VERSION 5.7 ;
  NOWIREEXTENSIONATPIN ON ;
  DIVIDERCHAR "/" ;
  BUSBITCHARS "[]" ;
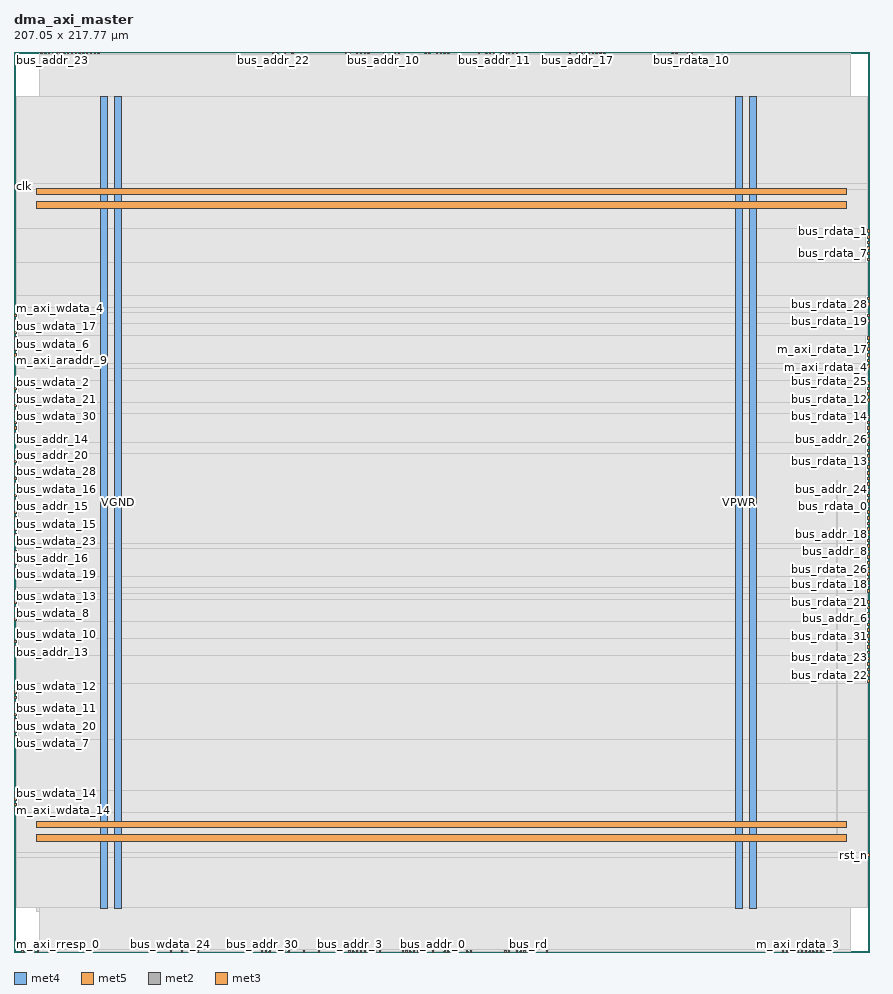
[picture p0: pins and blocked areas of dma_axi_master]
MACRO dma_axi_master
  CLASS BLOCK ;
  FOREIGN dma_axi_master ;
  ORIGIN 0.000 0.000 ;
  SIZE 207.050 BY 217.770 ;
  PIN VGND
    DIRECTION INOUT ;
    USE GROUND ;
    PORT
      LAYER met4 ;
        RECT 24.340 10.640 25.940 206.960 ;
    END
    PORT
      LAYER met4 ;
        RECT 177.940 10.640 179.540 206.960 ;
    END
    PORT
      LAYER met5 ;
        RECT 5.520 30.030 201.480 31.630 ;
    END
    PORT
      LAYER met5 ;
        RECT 5.520 183.210 201.480 184.810 ;
    END
  END VGND
  PIN VPWR
    DIRECTION INOUT ;
    USE POWER ;
    PORT
      LAYER met4 ;
        RECT 21.040 10.640 22.640 206.960 ;
    END
    PORT
      LAYER met4 ;
        RECT 174.640 10.640 176.240 206.960 ;
    END
    PORT
      LAYER met5 ;
        RECT 5.520 26.730 201.480 28.330 ;
    END
    PORT
      LAYER met5 ;
        RECT 5.520 179.910 201.480 181.510 ;
    END
  END VPWR
  PIN bus_addr_0
    DIRECTION INPUT ;
    USE SIGNAL ;
    ANTENNAGATEAREA 0.647700 ;
    ANTENNADIFFAREA 0.434700 ;
    PORT
      LAYER met2 ;
        RECT 101.290 0.000 101.570 0.280 ;
    END
  END bus_addr_0
  PIN bus_addr_1
    DIRECTION INPUT ;
    USE SIGNAL ;
    ANTENNAGATEAREA 0.647700 ;
    ANTENNADIFFAREA 0.434700 ;
    PORT
      LAYER met2 ;
        RECT 86.570 0.000 86.850 0.280 ;
    END
  END bus_addr_1
  PIN bus_addr_10
    DIRECTION INPUT ;
    USE SIGNAL ;
    ANTENNAGATEAREA 0.647700 ;
    ANTENNADIFFAREA 0.434700 ;
    PORT
      LAYER met2 ;
        RECT 89.330 217.490 89.610 217.770 ;
    END
  END bus_addr_10
  PIN bus_addr_11
    DIRECTION INPUT ;
    USE SIGNAL ;
    ANTENNAGATEAREA 0.647700 ;
    ANTENNADIFFAREA 0.434700 ;
    PORT
      LAYER met2 ;
        RECT 116.010 217.490 116.290 217.770 ;
    END
  END bus_addr_11
  PIN bus_addr_12
    DIRECTION INPUT ;
    USE SIGNAL ;
    ANTENNAGATEAREA 0.647700 ;
    ANTENNADIFFAREA 0.434700 ;
    PORT
      LAYER met2 ;
        RECT 99.450 217.490 99.730 217.770 ;
    END
  END bus_addr_12
  PIN bus_addr_13
    DIRECTION INPUT ;
    USE SIGNAL ;
    ANTENNAGATEAREA 0.647700 ;
    ANTENNADIFFAREA 0.434700 ;
    PORT
      LAYER met3 ;
        RECT 0.000 72.120 0.600 72.720 ;
    END
  END bus_addr_13
  PIN bus_addr_14
    DIRECTION INPUT ;
    USE SIGNAL ;
    ANTENNAGATEAREA 0.647700 ;
    ANTENNADIFFAREA 0.434700 ;
    PORT
      LAYER met3 ;
        RECT 0.000 123.800 0.600 124.400 ;
    END
  END bus_addr_14
  PIN bus_addr_15
    DIRECTION INPUT ;
    USE SIGNAL ;
    ANTENNAGATEAREA 0.647700 ;
    ANTENNADIFFAREA 0.434700 ;
    PORT
      LAYER met3 ;
        RECT 0.000 107.480 0.600 108.080 ;
    END
  END bus_addr_15
  PIN bus_addr_16
    DIRECTION INPUT ;
    USE SIGNAL ;
    ANTENNAGATEAREA 0.647700 ;
    ANTENNADIFFAREA 0.434700 ;
    PORT
      LAYER met3 ;
        RECT 0.000 96.600 0.600 97.200 ;
    END
  END bus_addr_16
  PIN bus_addr_17
    DIRECTION INPUT ;
    USE SIGNAL ;
    ANTENNAGATEAREA 0.647700 ;
    ANTENNADIFFAREA 0.434700 ;
    PORT
      LAYER met2 ;
        RECT 136.250 217.490 136.530 217.770 ;
    END
  END bus_addr_17
  PIN bus_addr_18
    DIRECTION INPUT ;
    USE SIGNAL ;
    ANTENNAGATEAREA 0.647700 ;
    ANTENNADIFFAREA 0.434700 ;
    PORT
      LAYER met3 ;
        RECT 206.450 100.680 207.050 101.280 ;
    END
  END bus_addr_18
  PIN bus_addr_19
    DIRECTION INPUT ;
    USE SIGNAL ;
    ANTENNAGATEAREA 0.647700 ;
    ANTENNADIFFAREA 0.434700 ;
    PORT
      LAYER met2 ;
        RECT 117.850 217.490 118.130 217.770 ;
    END
  END bus_addr_19
  PIN bus_addr_2
    DIRECTION INPUT ;
    USE SIGNAL ;
    ANTENNAGATEAREA 0.647700 ;
    ANTENNADIFFAREA 0.434700 ;
    PORT
      LAYER met2 ;
        RECT 106.810 0.000 107.090 0.280 ;
    END
  END bus_addr_2
  PIN bus_addr_20
    DIRECTION INPUT ;
    USE SIGNAL ;
    ANTENNAGATEAREA 0.647700 ;
    ANTENNADIFFAREA 0.434700 ;
    PORT
      LAYER met3 ;
        RECT 0.000 119.720 0.600 120.320 ;
    END
  END bus_addr_20
  PIN bus_addr_21
    DIRECTION INPUT ;
    USE SIGNAL ;
    ANTENNAGATEAREA 0.647700 ;
    ANTENNADIFFAREA 0.434700 ;
    PORT
      LAYER met2 ;
        RECT 138.090 217.490 138.370 217.770 ;
    END
  END bus_addr_21
  PIN bus_addr_22
    DIRECTION INPUT ;
    USE SIGNAL ;
    ANTENNAGATEAREA 0.647700 ;
    ANTENNADIFFAREA 0.434700 ;
    PORT
      LAYER met2 ;
        RECT 62.650 217.490 62.930 217.770 ;
    END
  END bus_addr_22
  PIN bus_addr_23
    DIRECTION INPUT ;
    USE SIGNAL ;
    ANTENNAGATEAREA 0.647700 ;
    ANTENNADIFFAREA 0.434700 ;
    PORT
      LAYER met2 ;
        RECT 6.530 217.490 6.810 217.770 ;
    END
  END bus_addr_23
  PIN bus_addr_24
    DIRECTION INPUT ;
    USE SIGNAL ;
    ANTENNAGATEAREA 0.647700 ;
    ANTENNADIFFAREA 0.434700 ;
    PORT
      LAYER met3 ;
        RECT 206.450 111.560 207.050 112.160 ;
    END
  END bus_addr_24
  PIN bus_addr_25
    DIRECTION INPUT ;
    USE SIGNAL ;
    ANTENNAGATEAREA 0.647700 ;
    ANTENNADIFFAREA 0.434700 ;
    PORT
      LAYER met2 ;
        RECT 112.330 217.490 112.610 217.770 ;
    END
  END bus_addr_25
  PIN bus_addr_26
    DIRECTION INPUT ;
    USE SIGNAL ;
    ANTENNAGATEAREA 0.647700 ;
    ANTENNADIFFAREA 0.434700 ;
    PORT
      LAYER met3 ;
        RECT 206.450 123.800 207.050 124.400 ;
    END
  END bus_addr_26
  PIN bus_addr_27
    DIRECTION INPUT ;
    USE SIGNAL ;
    ANTENNAGATEAREA 0.647700 ;
    ANTENNADIFFAREA 0.434700 ;
    PORT
      LAYER met2 ;
        RECT 80.130 217.490 80.410 217.770 ;
    END
  END bus_addr_27
  PIN bus_addr_28
    DIRECTION INPUT ;
    USE SIGNAL ;
    ANTENNAGATEAREA 0.647700 ;
    ANTENNADIFFAREA 0.434700 ;
    PORT
      LAYER met2 ;
        RECT 134.410 217.490 134.690 217.770 ;
    END
  END bus_addr_28
  PIN bus_addr_29
    DIRECTION INPUT ;
    USE SIGNAL ;
    ANTENNAGATEAREA 0.647700 ;
    ANTENNADIFFAREA 0.434700 ;
    PORT
      LAYER met2 ;
        RECT 81.050 217.490 81.330 217.770 ;
    END
  END bus_addr_29
  PIN bus_addr_3
    DIRECTION INPUT ;
    USE SIGNAL ;
    ANTENNAGATEAREA 0.647700 ;
    ANTENNADIFFAREA 0.434700 ;
    PORT
      LAYER met2 ;
        RECT 81.050 0.000 81.330 0.280 ;
    END
  END bus_addr_3
  PIN bus_addr_30
    DIRECTION INPUT ;
    USE SIGNAL ;
    ANTENNAGATEAREA 0.647700 ;
    ANTENNADIFFAREA 0.434700 ;
    PORT
      LAYER met2 ;
        RECT 59.890 0.000 60.170 0.280 ;
    END
  END bus_addr_30
  PIN bus_addr_31
    DIRECTION INPUT ;
    USE SIGNAL ;
    ANTENNAGATEAREA 0.647700 ;
    ANTENNADIFFAREA 0.434700 ;
    PORT
      LAYER met2 ;
        RECT 100.370 217.490 100.650 217.770 ;
    END
  END bus_addr_31
  PIN bus_addr_4
    DIRECTION INPUT ;
    USE SIGNAL ;
    ANTENNAGATEAREA 0.647700 ;
    ANTENNADIFFAREA 0.434700 ;
    PORT
      LAYER met2 ;
        RECT 81.970 0.000 82.250 0.280 ;
    END
  END bus_addr_4
  PIN bus_addr_5
    DIRECTION INPUT ;
    USE SIGNAL ;
    ANTENNAGATEAREA 0.647700 ;
    ANTENNADIFFAREA 0.434700 ;
    PORT
      LAYER met2 ;
        RECT 121.530 0.000 121.810 0.280 ;
    END
  END bus_addr_5
  PIN bus_addr_6
    DIRECTION INPUT ;
    USE SIGNAL ;
    ANTENNAGATEAREA 0.647700 ;
    ANTENNADIFFAREA 0.434700 ;
    PORT
      LAYER met3 ;
        RECT 206.450 80.280 207.050 80.880 ;
    END
  END bus_addr_6
  PIN bus_addr_7
    DIRECTION INPUT ;
    USE SIGNAL ;
    ANTENNAGATEAREA 0.647700 ;
    ANTENNADIFFAREA 0.434700 ;
    PORT
      LAYER met2 ;
        RECT 93.930 0.000 94.210 0.280 ;
    END
  END bus_addr_7
  PIN bus_addr_8
    DIRECTION INPUT ;
    USE SIGNAL ;
    ANTENNAGATEAREA 0.647700 ;
    ANTENNADIFFAREA 0.434700 ;
    PORT
      LAYER met3 ;
        RECT 206.450 96.600 207.050 97.200 ;
    END
  END bus_addr_8
  PIN bus_addr_9
    DIRECTION INPUT ;
    USE SIGNAL ;
    ANTENNAGATEAREA 0.647700 ;
    ANTENNADIFFAREA 0.434700 ;
    PORT
      LAYER met3 ;
        RECT 0.000 144.200 0.600 144.800 ;
    END
  END bus_addr_9
  PIN bus_rd
    DIRECTION INPUT ;
    USE SIGNAL ;
    ANTENNAGATEAREA 0.647700 ;
    ANTENNADIFFAREA 0.434700 ;
    PORT
      LAYER met2 ;
        RECT 124.290 0.000 124.570 0.280 ;
    END
  END bus_rd
  PIN bus_rdata_0
    DIRECTION OUTPUT ;
    USE SIGNAL ;
    ANTENNAGATEAREA 0.434700 ;
    ANTENNADIFFAREA 1.137600 ;
    PORT
      LAYER met3 ;
        RECT 206.450 107.480 207.050 108.080 ;
    END
  END bus_rdata_0
  PIN bus_rdata_1
    DIRECTION OUTPUT ;
    USE SIGNAL ;
    ANTENNAGATEAREA 0.434700 ;
    ANTENNADIFFAREA 1.137600 ;
    PORT
      LAYER met3 ;
        RECT 206.450 174.120 207.050 174.720 ;
    END
  END bus_rdata_1
  PIN bus_rdata_10
    DIRECTION OUTPUT ;
    USE SIGNAL ;
    ANTENNAGATEAREA 0.434700 ;
    ANTENNADIFFAREA 1.137600 ;
    PORT
      LAYER met2 ;
        RECT 163.850 217.490 164.130 217.770 ;
    END
  END bus_rdata_10
  PIN bus_rdata_11
    DIRECTION OUTPUT ;
    USE SIGNAL ;
    ANTENNAGATEAREA 0.434700 ;
    ANTENNADIFFAREA 1.137600 ;
    PORT
      LAYER met3 ;
        RECT 206.450 172.760 207.050 173.360 ;
    END
  END bus_rdata_11
  PIN bus_rdata_12
    DIRECTION OUTPUT ;
    USE SIGNAL ;
    ANTENNAGATEAREA 0.434700 ;
    ANTENNADIFFAREA 1.137600 ;
    PORT
      LAYER met3 ;
        RECT 206.450 133.320 207.050 133.920 ;
    END
  END bus_rdata_12
  PIN bus_rdata_13
    DIRECTION OUTPUT ;
    USE SIGNAL ;
    ANTENNAGATEAREA 0.434700 ;
    ANTENNADIFFAREA 1.137600 ;
    PORT
      LAYER met3 ;
        RECT 206.450 118.360 207.050 118.960 ;
    END
  END bus_rdata_13
  PIN bus_rdata_14
    DIRECTION OUTPUT ;
    USE SIGNAL ;
    ANTENNAGATEAREA 0.434700 ;
    ANTENNADIFFAREA 1.137600 ;
    PORT
      LAYER met3 ;
        RECT 206.450 129.240 207.050 129.840 ;
    END
  END bus_rdata_14
  PIN bus_rdata_15
    DIRECTION OUTPUT ;
    USE SIGNAL ;
    ANTENNAGATEAREA 0.434700 ;
    ANTENNADIFFAREA 1.137600 ;
    PORT
      LAYER met3 ;
        RECT 206.450 125.160 207.050 125.760 ;
    END
  END bus_rdata_15
  PIN bus_rdata_16
    DIRECTION OUTPUT ;
    USE SIGNAL ;
    ANTENNAGATEAREA 0.434700 ;
    ANTENNADIFFAREA 1.137600 ;
    PORT
      LAYER met2 ;
        RECT 196.050 0.000 196.330 0.280 ;
    END
  END bus_rdata_16
  PIN bus_rdata_17
    DIRECTION OUTPUT ;
    USE SIGNAL ;
    ANTENNAGATEAREA 0.434700 ;
    ANTENNADIFFAREA 1.137600 ;
    PORT
      LAYER met3 ;
        RECT 206.450 144.200 207.050 144.800 ;
    END
  END bus_rdata_17
  PIN bus_rdata_18
    DIRECTION OUTPUT ;
    USE SIGNAL ;
    ANTENNAGATEAREA 0.434700 ;
    ANTENNADIFFAREA 1.137600 ;
    PORT
      LAYER met3 ;
        RECT 206.450 87.080 207.050 87.680 ;
    END
  END bus_rdata_18
  PIN bus_rdata_19
    DIRECTION OUTPUT ;
    USE SIGNAL ;
    ANTENNAGATEAREA 0.434700 ;
    ANTENNADIFFAREA 1.137600 ;
    PORT
      LAYER met3 ;
        RECT 206.450 152.360 207.050 152.960 ;
    END
  END bus_rdata_19
  PIN bus_rdata_2
    DIRECTION OUTPUT ;
    USE SIGNAL ;
    ANTENNAGATEAREA 0.434700 ;
    ANTENNADIFFAREA 1.137600 ;
    PORT
      LAYER met3 ;
        RECT 206.450 104.760 207.050 105.360 ;
    END
  END bus_rdata_2
  PIN bus_rdata_20
    DIRECTION OUTPUT ;
    USE SIGNAL ;
    ANTENNAGATEAREA 0.434700 ;
    ANTENNADIFFAREA 1.137600 ;
    PORT
      LAYER met3 ;
        RECT 206.450 146.920 207.050 147.520 ;
    END
  END bus_rdata_20
  PIN bus_rdata_21
    DIRECTION OUTPUT ;
    USE SIGNAL ;
    ANTENNAGATEAREA 0.434700 ;
    ANTENNADIFFAREA 1.137600 ;
    PORT
      LAYER met3 ;
        RECT 206.450 84.360 207.050 84.960 ;
    END
  END bus_rdata_21
  PIN bus_rdata_22
    DIRECTION OUTPUT ;
    USE SIGNAL ;
    ANTENNAGATEAREA 0.434700 ;
    ANTENNADIFFAREA 1.137600 ;
    PORT
      LAYER met3 ;
        RECT 206.450 66.680 207.050 67.280 ;
    END
  END bus_rdata_22
  PIN bus_rdata_23
    DIRECTION OUTPUT ;
    USE SIGNAL ;
    ANTENNAGATEAREA 0.434700 ;
    ANTENNADIFFAREA 1.137600 ;
    PORT
      LAYER met3 ;
        RECT 206.450 69.400 207.050 70.000 ;
    END
  END bus_rdata_23
  PIN bus_rdata_24
    DIRECTION OUTPUT ;
    USE SIGNAL ;
    ANTENNAGATEAREA 0.434700 ;
    ANTENNADIFFAREA 1.137600 ;
    PORT
      LAYER met2 ;
        RECT 191.450 0.000 191.730 0.280 ;
    END
  END bus_rdata_24
  PIN bus_rdata_25
    DIRECTION OUTPUT ;
    USE SIGNAL ;
    ANTENNAGATEAREA 0.434700 ;
    ANTENNADIFFAREA 1.137600 ;
    PORT
      LAYER met3 ;
        RECT 206.450 136.040 207.050 136.640 ;
    END
  END bus_rdata_25
  PIN bus_rdata_26
    DIRECTION OUTPUT ;
    USE SIGNAL ;
    ANTENNAGATEAREA 0.434700 ;
    ANTENNADIFFAREA 1.137600 ;
    PORT
      LAYER met3 ;
        RECT 206.450 93.880 207.050 94.480 ;
    END
  END bus_rdata_26
  PIN bus_rdata_27
    DIRECTION OUTPUT ;
    USE SIGNAL ;
    ANTENNAGATEAREA 0.434700 ;
    ANTENNADIFFAREA 1.137600 ;
    PORT
      LAYER met2 ;
        RECT 162.930 217.490 163.210 217.770 ;
    END
  END bus_rdata_27
  PIN bus_rdata_28
    DIRECTION OUTPUT ;
    USE SIGNAL ;
    ANTENNAGATEAREA 0.434700 ;
    ANTENNADIFFAREA 1.137600 ;
    PORT
      LAYER met3 ;
        RECT 206.450 156.440 207.050 157.040 ;
    END
  END bus_rdata_28
  PIN bus_rdata_29
    DIRECTION OUTPUT ;
    USE SIGNAL ;
    ANTENNAGATEAREA 0.434700 ;
    ANTENNADIFFAREA 1.137600 ;
    PORT
      LAYER met3 ;
        RECT 206.450 70.760 207.050 71.360 ;
    END
  END bus_rdata_29
  PIN bus_rdata_3
    DIRECTION OUTPUT ;
    USE SIGNAL ;
    ANTENNAGATEAREA 0.434700 ;
    ANTENNADIFFAREA 1.137600 ;
    PORT
      LAYER met2 ;
        RECT 194.210 0.000 194.490 0.280 ;
    END
  END bus_rdata_3
  PIN bus_rdata_30
    DIRECTION OUTPUT ;
    USE SIGNAL ;
    ANTENNAGATEAREA 0.434700 ;
    ANTENNADIFFAREA 1.137600 ;
    PORT
      LAYER met2 ;
        RECT 193.290 0.000 193.570 0.280 ;
    END
  END bus_rdata_30
  PIN bus_rdata_31
    DIRECTION OUTPUT ;
    USE SIGNAL ;
    ANTENNAGATEAREA 0.434700 ;
    ANTENNADIFFAREA 1.137600 ;
    PORT
      LAYER met3 ;
        RECT 206.450 77.560 207.050 78.160 ;
    END
  END bus_rdata_31
  PIN bus_rdata_4
    DIRECTION OUTPUT ;
    USE SIGNAL ;
    ANTENNAGATEAREA 0.434700 ;
    ANTENNADIFFAREA 1.137600 ;
    PORT
      LAYER met3 ;
        RECT 206.450 141.480 207.050 142.080 ;
    END
  END bus_rdata_4
  PIN bus_rdata_5
    DIRECTION OUTPUT ;
    USE SIGNAL ;
    ANTENNAGATEAREA 0.434700 ;
    ANTENNADIFFAREA 1.137600 ;
    PORT
      LAYER met3 ;
        RECT 206.450 92.520 207.050 93.120 ;
    END
  END bus_rdata_5
  PIN bus_rdata_6
    DIRECTION OUTPUT ;
    USE SIGNAL ;
    ANTENNAGATEAREA 0.434700 ;
    ANTENNADIFFAREA 1.137600 ;
    PORT
      LAYER met3 ;
        RECT 206.450 108.840 207.050 109.440 ;
    END
  END bus_rdata_6
  PIN bus_rdata_7
    DIRECTION OUTPUT ;
    USE SIGNAL ;
    ANTENNAGATEAREA 0.434700 ;
    ANTENNADIFFAREA 1.137600 ;
    PORT
      LAYER met3 ;
        RECT 206.450 168.680 207.050 169.280 ;
    END
  END bus_rdata_7
  PIN bus_rdata_8
    DIRECTION OUTPUT ;
    USE SIGNAL ;
    ANTENNAGATEAREA 0.434700 ;
    ANTENNADIFFAREA 1.137600 ;
    PORT
      LAYER met3 ;
        RECT 206.450 73.480 207.050 74.080 ;
    END
  END bus_rdata_8
  PIN bus_rdata_9
    DIRECTION OUTPUT ;
    USE SIGNAL ;
    ANTENNAGATEAREA 0.434700 ;
    ANTENNADIFFAREA 1.137600 ;
    PORT
      LAYER met3 ;
        RECT 206.450 115.640 207.050 116.240 ;
    END
  END bus_rdata_9
  PIN bus_ready
    DIRECTION OUTPUT ;
    USE SIGNAL ;
    PORT
      LAYER met2 ;
        RECT 1.930 0.000 2.210 0.280 ;
    END
  END bus_ready
  PIN bus_wdata_0
    DIRECTION INPUT ;
    USE SIGNAL ;
    ANTENNAGATEAREA 0.647700 ;
    ANTENNADIFFAREA 0.434700 ;
    PORT
      LAYER met2 ;
        RECT 18.490 217.490 18.770 217.770 ;
    END
  END bus_wdata_0
  PIN bus_wdata_1
    DIRECTION INPUT ;
    USE SIGNAL ;
    ANTENNAGATEAREA 0.647700 ;
    ANTENNADIFFAREA 0.434700 ;
    PORT
      LAYER met3 ;
        RECT 0.000 99.320 0.600 99.920 ;
    END
  END bus_wdata_1
  PIN bus_wdata_10
    DIRECTION INPUT ;
    USE SIGNAL ;
    ANTENNAGATEAREA 0.647700 ;
    ANTENNADIFFAREA 0.434700 ;
    PORT
      LAYER met3 ;
        RECT 0.000 74.840 0.600 75.440 ;
    END
  END bus_wdata_10
  PIN bus_wdata_11
    DIRECTION INPUT ;
    USE SIGNAL ;
    ANTENNAGATEAREA 0.647700 ;
    ANTENNADIFFAREA 0.434700 ;
    PORT
      LAYER met3 ;
        RECT 0.000 58.520 0.600 59.120 ;
    END
  END bus_wdata_11
  PIN bus_wdata_12
    DIRECTION INPUT ;
    USE SIGNAL ;
    ANTENNAGATEAREA 0.647700 ;
    ANTENNADIFFAREA 0.434700 ;
    PORT
      LAYER met3 ;
        RECT 0.000 63.960 0.600 64.560 ;
    END
  END bus_wdata_12
  PIN bus_wdata_13
    DIRECTION INPUT ;
    USE SIGNAL ;
    ANTENNAGATEAREA 0.647700 ;
    ANTENNADIFFAREA 0.434700 ;
    PORT
      LAYER met3 ;
        RECT 0.000 85.720 0.600 86.320 ;
    END
  END bus_wdata_13
  PIN bus_wdata_14
    DIRECTION INPUT ;
    USE SIGNAL ;
    ANTENNAGATEAREA 0.647700 ;
    ANTENNADIFFAREA 0.434700 ;
    PORT
      LAYER met3 ;
        RECT 0.000 38.120 0.600 38.720 ;
    END
  END bus_wdata_14
  PIN bus_wdata_15
    DIRECTION INPUT ;
    USE SIGNAL ;
    ANTENNAGATEAREA 0.647700 ;
    ANTENNADIFFAREA 0.434700 ;
    PORT
      LAYER met3 ;
        RECT 0.000 104.760 0.600 105.360 ;
    END
  END bus_wdata_15
  PIN bus_wdata_16
    DIRECTION INPUT ;
    USE SIGNAL ;
    ANTENNAGATEAREA 0.647700 ;
    ANTENNADIFFAREA 0.434700 ;
    PORT
      LAYER met3 ;
        RECT 0.000 111.560 0.600 112.160 ;
    END
  END bus_wdata_16
  PIN bus_wdata_17
    DIRECTION INPUT ;
    USE SIGNAL ;
    ANTENNAGATEAREA 0.647700 ;
    ANTENNADIFFAREA 0.434700 ;
    PORT
      LAYER met3 ;
        RECT 0.000 151.000 0.600 151.600 ;
    END
  END bus_wdata_17
  PIN bus_wdata_18
    DIRECTION INPUT ;
    USE SIGNAL ;
    ANTENNAGATEAREA 0.647700 ;
    ANTENNADIFFAREA 0.434700 ;
    PORT
      LAYER met2 ;
        RECT 12.050 217.490 12.330 217.770 ;
    END
  END bus_wdata_18
  PIN bus_wdata_19
    DIRECTION INPUT ;
    USE SIGNAL ;
    ANTENNAGATEAREA 0.647700 ;
    ANTENNADIFFAREA 0.434700 ;
    PORT
      LAYER met3 ;
        RECT 0.000 91.160 0.600 91.760 ;
    END
  END bus_wdata_19
  PIN bus_wdata_2
    DIRECTION INPUT ;
    USE SIGNAL ;
    ANTENNAGATEAREA 0.647700 ;
    ANTENNADIFFAREA 0.434700 ;
    PORT
      LAYER met3 ;
        RECT 0.000 137.400 0.600 138.000 ;
    END
  END bus_wdata_2
  PIN bus_wdata_20
    DIRECTION INPUT ;
    USE SIGNAL ;
    ANTENNAGATEAREA 0.647700 ;
    ANTENNADIFFAREA 0.434700 ;
    PORT
      LAYER met3 ;
        RECT 0.000 55.800 0.600 56.400 ;
    END
  END bus_wdata_20
  PIN bus_wdata_21
    DIRECTION INPUT ;
    USE SIGNAL ;
    ANTENNAGATEAREA 0.647700 ;
    ANTENNADIFFAREA 0.434700 ;
    PORT
      LAYER met3 ;
        RECT 0.000 133.320 0.600 133.920 ;
    END
  END bus_wdata_21
  PIN bus_wdata_22
    DIRECTION INPUT ;
    USE SIGNAL ;
    ANTENNAGATEAREA 0.647700 ;
    ANTENNADIFFAREA 0.434700 ;
    PORT
      LAYER met2 ;
        RECT 14.810 217.490 15.090 217.770 ;
    END
  END bus_wdata_22
  PIN bus_wdata_23
    DIRECTION INPUT ;
    USE SIGNAL ;
    ANTENNAGATEAREA 0.647700 ;
    ANTENNADIFFAREA 0.434700 ;
    PORT
      LAYER met3 ;
        RECT 0.000 100.680 0.600 101.280 ;
    END
  END bus_wdata_23
  PIN bus_wdata_24
    DIRECTION INPUT ;
    USE SIGNAL ;
    ANTENNAGATEAREA 0.647700 ;
    ANTENNADIFFAREA 0.434700 ;
    PORT
      LAYER met2 ;
        RECT 37.810 0.000 38.090 0.280 ;
    END
  END bus_wdata_24
  PIN bus_wdata_25
    DIRECTION INPUT ;
    USE SIGNAL ;
    ANTENNAGATEAREA 0.647700 ;
    ANTENNADIFFAREA 0.434700 ;
    PORT
      LAYER met2 ;
        RECT 15.730 217.490 16.010 217.770 ;
    END
  END bus_wdata_25
  PIN bus_wdata_26
    DIRECTION INPUT ;
    USE SIGNAL ;
    ANTENNAGATEAREA 0.647700 ;
    ANTENNADIFFAREA 0.434700 ;
    PORT
      LAYER met3 ;
        RECT 0.000 36.760 0.600 37.360 ;
    END
  END bus_wdata_26
  PIN bus_wdata_27
    DIRECTION INPUT ;
    USE SIGNAL ;
    ANTENNAGATEAREA 0.647700 ;
    ANTENNADIFFAREA 0.434700 ;
    PORT
      LAYER met2 ;
        RECT 11.130 217.490 11.410 217.770 ;
    END
  END bus_wdata_27
  PIN bus_wdata_28
    DIRECTION INPUT ;
    USE SIGNAL ;
    ANTENNAGATEAREA 0.647700 ;
    ANTENNADIFFAREA 0.434700 ;
    PORT
      LAYER met3 ;
        RECT 0.000 114.280 0.600 114.880 ;
    END
  END bus_wdata_28
  PIN bus_wdata_29
    DIRECTION INPUT ;
    USE SIGNAL ;
    ANTENNAGATEAREA 0.647700 ;
    ANTENNADIFFAREA 0.434700 ;
    PORT
      LAYER met3 ;
        RECT 0.000 131.960 0.600 132.560 ;
    END
  END bus_wdata_29
  PIN bus_wdata_3
    DIRECTION INPUT ;
    USE SIGNAL ;
    ANTENNAGATEAREA 0.647700 ;
    ANTENNADIFFAREA 0.434700 ;
    PORT
      LAYER met2 ;
        RECT 16.650 217.490 16.930 217.770 ;
    END
  END bus_wdata_3
  PIN bus_wdata_30
    DIRECTION INPUT ;
    USE SIGNAL ;
    ANTENNAGATEAREA 0.647700 ;
    ANTENNADIFFAREA 0.434700 ;
    PORT
      LAYER met3 ;
        RECT 0.000 129.240 0.600 129.840 ;
    END
  END bus_wdata_30
  PIN bus_wdata_31
    DIRECTION INPUT ;
    USE SIGNAL ;
    ANTENNAGATEAREA 0.647700 ;
    ANTENNADIFFAREA 0.434700 ;
    PORT
      LAYER met3 ;
        RECT 0.000 84.360 0.600 84.960 ;
    END
  END bus_wdata_31
  PIN bus_wdata_4
    DIRECTION INPUT ;
    USE SIGNAL ;
    ANTENNAGATEAREA 0.647700 ;
    ANTENNADIFFAREA 0.434700 ;
    PORT
      LAYER met3 ;
        RECT 0.000 152.360 0.600 152.960 ;
    END
  END bus_wdata_4
  PIN bus_wdata_5
    DIRECTION INPUT ;
    USE SIGNAL ;
    ANTENNAGATEAREA 0.647700 ;
    ANTENNADIFFAREA 0.434700 ;
    PORT
      LAYER met3 ;
        RECT 0.000 61.240 0.600 61.840 ;
    END
  END bus_wdata_5
  PIN bus_wdata_6
    DIRECTION INPUT ;
    USE SIGNAL ;
    ANTENNAGATEAREA 0.647700 ;
    ANTENNADIFFAREA 0.434700 ;
    PORT
      LAYER met3 ;
        RECT 0.000 148.280 0.600 148.880 ;
    END
  END bus_wdata_6
  PIN bus_wdata_7
    DIRECTION INPUT ;
    USE SIGNAL ;
    ANTENNAGATEAREA 0.647700 ;
    ANTENNADIFFAREA 0.434700 ;
    PORT
      LAYER met3 ;
        RECT 0.000 51.720 0.600 52.320 ;
    END
  END bus_wdata_7
  PIN bus_wdata_8
    DIRECTION INPUT ;
    USE SIGNAL ;
    ANTENNAGATEAREA 0.647700 ;
    ANTENNADIFFAREA 0.434700 ;
    PORT
      LAYER met3 ;
        RECT 0.000 81.640 0.600 82.240 ;
    END
  END bus_wdata_8
  PIN bus_wdata_9
    DIRECTION INPUT ;
    USE SIGNAL ;
    ANTENNAGATEAREA 0.647700 ;
    ANTENNADIFFAREA 0.434700 ;
    PORT
      LAYER met2 ;
        RECT 8.370 217.490 8.650 217.770 ;
    END
  END bus_wdata_9
  PIN bus_wr
    DIRECTION INPUT ;
    USE SIGNAL ;
    ANTENNAGATEAREA 0.647700 ;
    ANTENNADIFFAREA 0.434700 ;
    PORT
      LAYER met2 ;
        RECT 122.450 0.000 122.730 0.280 ;
    END
  END bus_wr
  PIN clk
    DIRECTION INPUT ;
    USE SIGNAL ;
    ANTENNAGATEAREA 1.286700 ;
    ANTENNADIFFAREA 0.434700 ;
    PORT
      LAYER met3 ;
        RECT 0.000 185.000 0.600 185.600 ;
    END
  END clk
  PIN m_axi_araddr_0
    DIRECTION OUTPUT ;
    USE SIGNAL ;
    ANTENNAGATEAREA 0.434700 ;
    ANTENNADIFFAREA 1.137600 ;
    PORT
      LAYER met2 ;
        RECT 104.050 0.000 104.330 0.280 ;
    END
  END m_axi_araddr_0
  PIN m_axi_araddr_1
    DIRECTION OUTPUT ;
    USE SIGNAL ;
    ANTENNAGATEAREA 0.434700 ;
    ANTENNADIFFAREA 1.137600 ;
    PORT
      LAYER met2 ;
        RECT 87.490 0.000 87.770 0.280 ;
    END
  END m_axi_araddr_1
  PIN m_axi_araddr_10
    DIRECTION OUTPUT ;
    USE SIGNAL ;
    ANTENNAGATEAREA 0.434700 ;
    ANTENNADIFFAREA 1.137600 ;
    PORT
      LAYER met2 ;
        RECT 93.010 217.490 93.290 217.770 ;
    END
  END m_axi_araddr_10
  PIN m_axi_araddr_11
    DIRECTION OUTPUT ;
    USE SIGNAL ;
    ANTENNAGATEAREA 0.434700 ;
    ANTENNADIFFAREA 1.137600 ;
    PORT
      LAYER met2 ;
        RECT 119.690 217.490 119.970 217.770 ;
    END
  END m_axi_araddr_11
  PIN m_axi_araddr_12
    DIRECTION OUTPUT ;
    USE SIGNAL ;
    ANTENNAGATEAREA 0.434700 ;
    ANTENNADIFFAREA 1.137600 ;
    PORT
      LAYER met2 ;
        RECT 103.130 217.490 103.410 217.770 ;
    END
  END m_axi_araddr_12
  PIN m_axi_araddr_13
    DIRECTION OUTPUT ;
    USE SIGNAL ;
    ANTENNAGATEAREA 0.434700 ;
    ANTENNADIFFAREA 1.137600 ;
    PORT
      LAYER met2 ;
        RECT 66.330 0.000 66.610 0.280 ;
    END
  END m_axi_araddr_13
  PIN m_axi_araddr_14
    DIRECTION OUTPUT ;
    USE SIGNAL ;
    ANTENNAGATEAREA 0.434700 ;
    ANTENNADIFFAREA 1.137600 ;
    PORT
      LAYER met3 ;
        RECT 0.000 126.520 0.600 127.120 ;
    END
  END m_axi_araddr_14
  PIN m_axi_araddr_15
    DIRECTION OUTPUT ;
    USE SIGNAL ;
    ANTENNAGATEAREA 0.434700 ;
    ANTENNADIFFAREA 1.137600 ;
    PORT
      LAYER met3 ;
        RECT 0.000 108.840 0.600 109.440 ;
    END
  END m_axi_araddr_15
  PIN m_axi_araddr_16
    DIRECTION OUTPUT ;
    USE SIGNAL ;
    ANTENNAGATEAREA 0.434700 ;
    ANTENNADIFFAREA 1.137600 ;
    PORT
      LAYER met3 ;
        RECT 0.000 93.880 0.600 94.480 ;
    END
  END m_axi_araddr_16
  PIN m_axi_araddr_17
    DIRECTION OUTPUT ;
    USE SIGNAL ;
    ANTENNAGATEAREA 0.434700 ;
    ANTENNADIFFAREA 1.137600 ;
    PORT
      LAYER met2 ;
        RECT 140.850 217.490 141.130 217.770 ;
    END
  END m_axi_araddr_17
  PIN m_axi_araddr_18
    DIRECTION OUTPUT ;
    USE SIGNAL ;
    ANTENNAGATEAREA 0.434700 ;
    ANTENNADIFFAREA 1.137600 ;
    PORT
      LAYER met3 ;
        RECT 206.450 99.320 207.050 99.920 ;
    END
  END m_axi_araddr_18
  PIN m_axi_araddr_19
    DIRECTION OUTPUT ;
    USE SIGNAL ;
    ANTENNAGATEAREA 0.434700 ;
    ANTENNADIFFAREA 1.137600 ;
    PORT
      LAYER met2 ;
        RECT 121.530 217.490 121.810 217.770 ;
    END
  END m_axi_araddr_19
  PIN m_axi_araddr_2
    DIRECTION OUTPUT ;
    USE SIGNAL ;
    ANTENNAGATEAREA 0.434700 ;
    ANTENNADIFFAREA 1.137600 ;
    PORT
      LAYER met2 ;
        RECT 110.490 0.000 110.770 0.280 ;
    END
  END m_axi_araddr_2
  PIN m_axi_araddr_20
    DIRECTION OUTPUT ;
    USE SIGNAL ;
    ANTENNAGATEAREA 0.434700 ;
    ANTENNADIFFAREA 1.137600 ;
    PORT
      LAYER met3 ;
        RECT 0.000 118.360 0.600 118.960 ;
    END
  END m_axi_araddr_20
  PIN m_axi_araddr_21
    DIRECTION OUTPUT ;
    USE SIGNAL ;
    ANTENNAGATEAREA 0.434700 ;
    ANTENNADIFFAREA 1.137600 ;
    PORT
      LAYER met2 ;
        RECT 142.690 217.490 142.970 217.770 ;
    END
  END m_axi_araddr_21
  PIN m_axi_araddr_22
    DIRECTION OUTPUT ;
    USE SIGNAL ;
    ANTENNAGATEAREA 0.434700 ;
    ANTENNADIFFAREA 1.137600 ;
    PORT
      LAYER met2 ;
        RECT 67.250 217.490 67.530 217.770 ;
    END
  END m_axi_araddr_22
  PIN m_axi_araddr_23
    DIRECTION OUTPUT ;
    USE SIGNAL ;
    ANTENNAGATEAREA 0.434700 ;
    ANTENNADIFFAREA 1.137600 ;
    PORT
      LAYER met2 ;
        RECT 63.570 217.490 63.850 217.770 ;
    END
  END m_axi_araddr_23
  PIN m_axi_araddr_24
    DIRECTION OUTPUT ;
    USE SIGNAL ;
    ANTENNAGATEAREA 0.434700 ;
    ANTENNADIFFAREA 1.137600 ;
    PORT
      LAYER met3 ;
        RECT 206.450 112.920 207.050 113.520 ;
    END
  END m_axi_araddr_24
  PIN m_axi_araddr_25
    DIRECTION OUTPUT ;
    USE SIGNAL ;
    ANTENNAGATEAREA 0.434700 ;
    ANTENNADIFFAREA 1.137600 ;
    PORT
      LAYER met2 ;
        RECT 114.170 217.490 114.450 217.770 ;
    END
  END m_axi_araddr_25
  PIN m_axi_araddr_26
    DIRECTION OUTPUT ;
    USE SIGNAL ;
    ANTENNAGATEAREA 0.434700 ;
    ANTENNADIFFAREA 1.137600 ;
    PORT
      LAYER met3 ;
        RECT 206.450 121.080 207.050 121.680 ;
    END
  END m_axi_araddr_26
  PIN m_axi_araddr_27
    DIRECTION OUTPUT ;
    USE SIGNAL ;
    ANTENNAGATEAREA 0.434700 ;
    ANTENNADIFFAREA 1.137600 ;
    PORT
      LAYER met2 ;
        RECT 82.890 217.490 83.170 217.770 ;
    END
  END m_axi_araddr_27
  PIN m_axi_araddr_28
    DIRECTION OUTPUT ;
    USE SIGNAL ;
    ANTENNAGATEAREA 0.434700 ;
    ANTENNADIFFAREA 1.137600 ;
    PORT
      LAYER met2 ;
        RECT 137.170 217.490 137.450 217.770 ;
    END
  END m_axi_araddr_28
  PIN m_axi_araddr_29
    DIRECTION OUTPUT ;
    USE SIGNAL ;
    ANTENNAGATEAREA 0.434700 ;
    ANTENNADIFFAREA 1.137600 ;
    PORT
      LAYER met2 ;
        RECT 83.810 217.490 84.090 217.770 ;
    END
  END m_axi_araddr_29
  PIN m_axi_araddr_3
    DIRECTION OUTPUT ;
    USE SIGNAL ;
    ANTENNAGATEAREA 0.434700 ;
    ANTENNADIFFAREA 1.137600 ;
    PORT
      LAYER met2 ;
        RECT 82.890 0.000 83.170 0.280 ;
    END
  END m_axi_araddr_3
  PIN m_axi_araddr_30
    DIRECTION OUTPUT ;
    USE SIGNAL ;
    ANTENNAGATEAREA 0.434700 ;
    ANTENNADIFFAREA 1.137600 ;
    PORT
      LAYER met2 ;
        RECT 65.410 0.000 65.690 0.280 ;
    END
  END m_axi_araddr_30
  PIN m_axi_araddr_31
    DIRECTION OUTPUT ;
    USE SIGNAL ;
    ANTENNAGATEAREA 0.434700 ;
    ANTENNADIFFAREA 1.137600 ;
    PORT
      LAYER met2 ;
        RECT 104.050 217.490 104.330 217.770 ;
    END
  END m_axi_araddr_31
  PIN m_axi_araddr_4
    DIRECTION OUTPUT ;
    USE SIGNAL ;
    ANTENNAGATEAREA 0.434700 ;
    ANTENNADIFFAREA 1.137600 ;
    PORT
      LAYER met2 ;
        RECT 85.650 0.000 85.930 0.280 ;
    END
  END m_axi_araddr_4
  PIN m_axi_araddr_5
    DIRECTION OUTPUT ;
    USE SIGNAL ;
    ANTENNAGATEAREA 0.434700 ;
    ANTENNADIFFAREA 1.137600 ;
    PORT
      LAYER met2 ;
        RECT 128.890 0.000 129.170 0.280 ;
    END
  END m_axi_araddr_5
  PIN m_axi_araddr_6
    DIRECTION OUTPUT ;
    USE SIGNAL ;
    ANTENNAGATEAREA 0.434700 ;
    ANTENNADIFFAREA 1.137600 ;
    PORT
      LAYER met3 ;
        RECT 206.450 81.640 207.050 82.240 ;
    END
  END m_axi_araddr_6
  PIN m_axi_araddr_7
    DIRECTION OUTPUT ;
    USE SIGNAL ;
    ANTENNAGATEAREA 0.434700 ;
    ANTENNADIFFAREA 1.137600 ;
    PORT
      LAYER met2 ;
        RECT 99.450 0.000 99.730 0.280 ;
    END
  END m_axi_araddr_7
  PIN m_axi_araddr_8
    DIRECTION OUTPUT ;
    USE SIGNAL ;
    ANTENNAGATEAREA 0.434700 ;
    ANTENNADIFFAREA 1.137600 ;
    PORT
      LAYER met3 ;
        RECT 206.450 95.240 207.050 95.840 ;
    END
  END m_axi_araddr_8
  PIN m_axi_araddr_9
    DIRECTION OUTPUT ;
    USE SIGNAL ;
    ANTENNAGATEAREA 0.434700 ;
    ANTENNADIFFAREA 1.137600 ;
    PORT
      LAYER met3 ;
        RECT 0.000 142.840 0.600 143.440 ;
    END
  END m_axi_araddr_9
  PIN m_axi_arready
    DIRECTION INPUT ;
    USE SIGNAL ;
    ANTENNAGATEAREA 0.647700 ;
    ANTENNADIFFAREA 0.434700 ;
    PORT
      LAYER met2 ;
        RECT 190.530 0.000 190.810 0.280 ;
    END
  END m_axi_arready
  PIN m_axi_arvalid
    DIRECTION OUTPUT ;
    USE SIGNAL ;
    ANTENNAGATEAREA 0.434700 ;
    ANTENNADIFFAREA 1.137600 ;
    PORT
      LAYER met2 ;
        RECT 186.850 0.000 187.130 0.280 ;
    END
  END m_axi_arvalid
  PIN m_axi_awaddr_0
    DIRECTION OUTPUT ;
    USE SIGNAL ;
    ANTENNAGATEAREA 0.434700 ;
    ANTENNADIFFAREA 1.137600 ;
    PORT
      LAYER met2 ;
        RECT 104.970 0.000 105.250 0.280 ;
    END
  END m_axi_awaddr_0
  PIN m_axi_awaddr_1
    DIRECTION OUTPUT ;
    USE SIGNAL ;
    ANTENNAGATEAREA 0.434700 ;
    ANTENNADIFFAREA 1.137600 ;
    PORT
      LAYER met2 ;
        RECT 88.410 0.000 88.690 0.280 ;
    END
  END m_axi_awaddr_1
  PIN m_axi_awaddr_10
    DIRECTION OUTPUT ;
    USE SIGNAL ;
    ANTENNAGATEAREA 0.434700 ;
    ANTENNADIFFAREA 1.137600 ;
    PORT
      LAYER met2 ;
        RECT 92.090 217.490 92.370 217.770 ;
    END
  END m_axi_awaddr_10
  PIN m_axi_awaddr_11
    DIRECTION OUTPUT ;
    USE SIGNAL ;
    ANTENNAGATEAREA 0.434700 ;
    ANTENNADIFFAREA 1.137600 ;
    PORT
      LAYER met2 ;
        RECT 118.770 217.490 119.050 217.770 ;
    END
  END m_axi_awaddr_11
  PIN m_axi_awaddr_12
    DIRECTION OUTPUT ;
    USE SIGNAL ;
    ANTENNAGATEAREA 0.434700 ;
    ANTENNADIFFAREA 1.137600 ;
    PORT
      LAYER met2 ;
        RECT 102.210 217.490 102.490 217.770 ;
    END
  END m_axi_awaddr_12
  PIN m_axi_awaddr_13
    DIRECTION OUTPUT ;
    USE SIGNAL ;
    ANTENNAGATEAREA 0.434700 ;
    ANTENNADIFFAREA 1.137600 ;
    PORT
      LAYER met2 ;
        RECT 64.490 0.000 64.770 0.280 ;
    END
  END m_axi_awaddr_13
  PIN m_axi_awaddr_14
    DIRECTION OUTPUT ;
    USE SIGNAL ;
    ANTENNAGATEAREA 0.434700 ;
    ANTENNADIFFAREA 1.137600 ;
    PORT
      LAYER met3 ;
        RECT 0.000 125.160 0.600 125.760 ;
    END
  END m_axi_awaddr_14
  PIN m_axi_awaddr_15
    DIRECTION OUTPUT ;
    USE SIGNAL ;
    ANTENNAGATEAREA 0.434700 ;
    ANTENNADIFFAREA 1.137600 ;
    PORT
      LAYER met3 ;
        RECT 0.000 110.200 0.600 110.800 ;
    END
  END m_axi_awaddr_15
  PIN m_axi_awaddr_16
    DIRECTION OUTPUT ;
    USE SIGNAL ;
    ANTENNAGATEAREA 0.434700 ;
    ANTENNADIFFAREA 1.137600 ;
    PORT
      LAYER met3 ;
        RECT 0.000 95.240 0.600 95.840 ;
    END
  END m_axi_awaddr_16
  PIN m_axi_awaddr_17
    DIRECTION OUTPUT ;
    USE SIGNAL ;
    ANTENNAGATEAREA 0.434700 ;
    ANTENNADIFFAREA 1.137600 ;
    PORT
      LAYER met2 ;
        RECT 139.930 217.490 140.210 217.770 ;
    END
  END m_axi_awaddr_17
  PIN m_axi_awaddr_18
    DIRECTION OUTPUT ;
    USE SIGNAL ;
    ANTENNAGATEAREA 0.434700 ;
    ANTENNADIFFAREA 1.137600 ;
    PORT
      LAYER met3 ;
        RECT 206.450 102.040 207.050 102.640 ;
    END
  END m_axi_awaddr_18
  PIN m_axi_awaddr_19
    DIRECTION OUTPUT ;
    USE SIGNAL ;
    ANTENNAGATEAREA 0.434700 ;
    ANTENNADIFFAREA 1.137600 ;
    PORT
      LAYER met2 ;
        RECT 120.610 217.490 120.890 217.770 ;
    END
  END m_axi_awaddr_19
  PIN m_axi_awaddr_2
    DIRECTION OUTPUT ;
    USE SIGNAL ;
    ANTENNAGATEAREA 0.434700 ;
    ANTENNADIFFAREA 1.137600 ;
    PORT
      LAYER met2 ;
        RECT 109.570 0.000 109.850 0.280 ;
    END
  END m_axi_awaddr_2
  PIN m_axi_awaddr_20
    DIRECTION OUTPUT ;
    USE SIGNAL ;
    ANTENNAGATEAREA 0.434700 ;
    ANTENNADIFFAREA 1.137600 ;
    PORT
      LAYER met3 ;
        RECT 0.000 117.000 0.600 117.600 ;
    END
  END m_axi_awaddr_20
  PIN m_axi_awaddr_21
    DIRECTION OUTPUT ;
    USE SIGNAL ;
    ANTENNAGATEAREA 0.434700 ;
    ANTENNADIFFAREA 1.137600 ;
    PORT
      LAYER met2 ;
        RECT 141.770 217.490 142.050 217.770 ;
    END
  END m_axi_awaddr_21
  PIN m_axi_awaddr_22
    DIRECTION OUTPUT ;
    USE SIGNAL ;
    ANTENNAGATEAREA 0.434700 ;
    ANTENNADIFFAREA 1.137600 ;
    PORT
      LAYER met2 ;
        RECT 65.410 217.490 65.690 217.770 ;
    END
  END m_axi_awaddr_22
  PIN m_axi_awaddr_23
    DIRECTION OUTPUT ;
    USE SIGNAL ;
    ANTENNAGATEAREA 0.434700 ;
    ANTENNADIFFAREA 1.137600 ;
    PORT
      LAYER met2 ;
        RECT 19.410 217.490 19.690 217.770 ;
    END
  END m_axi_awaddr_23
  PIN m_axi_awaddr_24
    DIRECTION OUTPUT ;
    USE SIGNAL ;
    ANTENNAGATEAREA 0.434700 ;
    ANTENNADIFFAREA 1.137600 ;
    PORT
      LAYER met3 ;
        RECT 206.450 114.280 207.050 114.880 ;
    END
  END m_axi_awaddr_24
  PIN m_axi_awaddr_25
    DIRECTION OUTPUT ;
    USE SIGNAL ;
    ANTENNAGATEAREA 0.434700 ;
    ANTENNADIFFAREA 1.137600 ;
    PORT
      LAYER met2 ;
        RECT 115.090 217.490 115.370 217.770 ;
    END
  END m_axi_awaddr_25
  PIN m_axi_awaddr_26
    DIRECTION OUTPUT ;
    USE SIGNAL ;
    ANTENNAGATEAREA 0.434700 ;
    ANTENNADIFFAREA 1.137600 ;
    PORT
      LAYER met3 ;
        RECT 206.450 122.440 207.050 123.040 ;
    END
  END m_axi_awaddr_26
  PIN m_axi_awaddr_27
    DIRECTION OUTPUT ;
    USE SIGNAL ;
    ANTENNAGATEAREA 0.434700 ;
    ANTENNADIFFAREA 1.137600 ;
    PORT
      LAYER met2 ;
        RECT 84.730 217.490 85.010 217.770 ;
    END
  END m_axi_awaddr_27
  PIN m_axi_awaddr_28
    DIRECTION OUTPUT ;
    USE SIGNAL ;
    ANTENNAGATEAREA 0.434700 ;
    ANTENNADIFFAREA 1.137600 ;
    PORT
      LAYER met2 ;
        RECT 139.010 217.490 139.290 217.770 ;
    END
  END m_axi_awaddr_28
  PIN m_axi_awaddr_29
    DIRECTION OUTPUT ;
    USE SIGNAL ;
    ANTENNAGATEAREA 0.434700 ;
    ANTENNADIFFAREA 1.137600 ;
    PORT
      LAYER met2 ;
        RECT 85.650 217.490 85.930 217.770 ;
    END
  END m_axi_awaddr_29
  PIN m_axi_awaddr_3
    DIRECTION OUTPUT ;
    USE SIGNAL ;
    ANTENNAGATEAREA 0.434700 ;
    ANTENNADIFFAREA 1.137600 ;
    PORT
      LAYER met2 ;
        RECT 83.810 0.000 84.090 0.280 ;
    END
  END m_axi_awaddr_3
  PIN m_axi_awaddr_30
    DIRECTION OUTPUT ;
    USE SIGNAL ;
    ANTENNAGATEAREA 0.434700 ;
    ANTENNADIFFAREA 1.137600 ;
    PORT
      LAYER met2 ;
        RECT 61.730 0.000 62.010 0.280 ;
    END
  END m_axi_awaddr_30
  PIN m_axi_awaddr_31
    DIRECTION OUTPUT ;
    USE SIGNAL ;
    ANTENNAGATEAREA 0.434700 ;
    ANTENNADIFFAREA 1.137600 ;
    PORT
      LAYER met2 ;
        RECT 104.970 217.490 105.250 217.770 ;
    END
  END m_axi_awaddr_31
  PIN m_axi_awaddr_4
    DIRECTION OUTPUT ;
    USE SIGNAL ;
    ANTENNAGATEAREA 0.434700 ;
    ANTENNADIFFAREA 1.137600 ;
    PORT
      LAYER met2 ;
        RECT 84.730 0.000 85.010 0.280 ;
    END
  END m_axi_awaddr_4
  PIN m_axi_awaddr_5
    DIRECTION OUTPUT ;
    USE SIGNAL ;
    ANTENNAGATEAREA 0.434700 ;
    ANTENNADIFFAREA 1.137600 ;
    PORT
      LAYER met2 ;
        RECT 123.370 0.000 123.650 0.280 ;
    END
  END m_axi_awaddr_5
  PIN m_axi_awaddr_6
    DIRECTION OUTPUT ;
    USE SIGNAL ;
    ANTENNAGATEAREA 0.434700 ;
    ANTENNADIFFAREA 1.137600 ;
    PORT
      LAYER met3 ;
        RECT 206.450 78.920 207.050 79.520 ;
    END
  END m_axi_awaddr_6
  PIN m_axi_awaddr_7
    DIRECTION OUTPUT ;
    USE SIGNAL ;
    ANTENNAGATEAREA 0.434700 ;
    ANTENNADIFFAREA 1.137600 ;
    PORT
      LAYER met2 ;
        RECT 97.610 0.000 97.890 0.280 ;
    END
  END m_axi_awaddr_7
  PIN m_axi_awaddr_8
    DIRECTION OUTPUT ;
    USE SIGNAL ;
    ANTENNAGATEAREA 0.434700 ;
    ANTENNADIFFAREA 1.137600 ;
    PORT
      LAYER met3 ;
        RECT 206.450 97.960 207.050 98.560 ;
    END
  END m_axi_awaddr_8
  PIN m_axi_awaddr_9
    DIRECTION OUTPUT ;
    USE SIGNAL ;
    ANTENNAGATEAREA 0.434700 ;
    ANTENNADIFFAREA 1.137600 ;
    PORT
      LAYER met3 ;
        RECT 0.000 145.560 0.600 146.160 ;
    END
  END m_axi_awaddr_9
  PIN m_axi_awready
    DIRECTION INPUT ;
    USE SIGNAL ;
    ANTENNAGATEAREA 0.647700 ;
    ANTENNADIFFAREA 0.434700 ;
    PORT
      LAYER met2 ;
        RECT 119.690 0.000 119.970 0.280 ;
    END
  END m_axi_awready
  PIN m_axi_awvalid
    DIRECTION OUTPUT ;
    USE SIGNAL ;
    ANTENNAGATEAREA 0.434700 ;
    ANTENNADIFFAREA 1.137600 ;
    PORT
      LAYER met2 ;
        RECT 118.770 0.000 119.050 0.280 ;
    END
  END m_axi_awvalid
  PIN m_axi_bready
    DIRECTION OUTPUT ;
    USE SIGNAL ;
    ANTENNAGATEAREA 0.434700 ;
    ANTENNADIFFAREA 1.137600 ;
    PORT
      LAYER met2 ;
        RECT 98.530 0.000 98.810 0.280 ;
    END
  END m_axi_bready
  PIN m_axi_bresp_0
    DIRECTION INPUT ;
    USE SIGNAL ;
    PORT
      LAYER met2 ;
        RECT 2.850 0.000 3.130 0.280 ;
    END
  END m_axi_bresp_0
  PIN m_axi_bresp_1
    DIRECTION INPUT ;
    USE SIGNAL ;
    PORT
      LAYER met2 ;
        RECT 3.770 0.000 4.050 0.280 ;
    END
  END m_axi_bresp_1
  PIN m_axi_bvalid
    DIRECTION INPUT ;
    USE SIGNAL ;
    ANTENNAGATEAREA 0.647700 ;
    ANTENNADIFFAREA 0.434700 ;
    PORT
      LAYER met2 ;
        RECT 96.690 0.000 96.970 0.280 ;
    END
  END m_axi_bvalid
  PIN m_axi_rdata_0
    DIRECTION INPUT ;
    USE SIGNAL ;
    ANTENNAGATEAREA 0.647700 ;
    ANTENNADIFFAREA 0.434700 ;
    PORT
      LAYER met3 ;
        RECT 206.450 106.120 207.050 106.720 ;
    END
  END m_axi_rdata_0
  PIN m_axi_rdata_1
    DIRECTION INPUT ;
    USE SIGNAL ;
    ANTENNAGATEAREA 0.647700 ;
    ANTENNADIFFAREA 0.434700 ;
    PORT
      LAYER met3 ;
        RECT 206.450 171.400 207.050 172.000 ;
    END
  END m_axi_rdata_1
  PIN m_axi_rdata_10
    DIRECTION INPUT ;
    USE SIGNAL ;
    ANTENNAGATEAREA 0.647700 ;
    ANTENNADIFFAREA 0.434700 ;
    PORT
      LAYER met2 ;
        RECT 160.170 217.490 160.450 217.770 ;
    END
  END m_axi_rdata_10
  PIN m_axi_rdata_11
    DIRECTION INPUT ;
    USE SIGNAL ;
    ANTENNAGATEAREA 0.647700 ;
    ANTENNADIFFAREA 0.434700 ;
    PORT
      LAYER met3 ;
        RECT 206.450 170.040 207.050 170.640 ;
    END
  END m_axi_rdata_11
  PIN m_axi_rdata_12
    DIRECTION INPUT ;
    USE SIGNAL ;
    ANTENNAGATEAREA 0.647700 ;
    ANTENNADIFFAREA 0.434700 ;
    PORT
      LAYER met3 ;
        RECT 206.450 134.680 207.050 135.280 ;
    END
  END m_axi_rdata_12
  PIN m_axi_rdata_13
    DIRECTION INPUT ;
    USE SIGNAL ;
    ANTENNAGATEAREA 0.647700 ;
    ANTENNADIFFAREA 0.434700 ;
    PORT
      LAYER met3 ;
        RECT 206.450 117.000 207.050 117.600 ;
    END
  END m_axi_rdata_13
  PIN m_axi_rdata_14
    DIRECTION INPUT ;
    USE SIGNAL ;
    ANTENNAGATEAREA 0.647700 ;
    ANTENNADIFFAREA 0.434700 ;
    PORT
      LAYER met3 ;
        RECT 206.450 127.880 207.050 128.480 ;
    END
  END m_axi_rdata_14
  PIN m_axi_rdata_15
    DIRECTION INPUT ;
    USE SIGNAL ;
    ANTENNAGATEAREA 0.647700 ;
    ANTENNADIFFAREA 0.434700 ;
    PORT
      LAYER met3 ;
        RECT 206.450 126.520 207.050 127.120 ;
    END
  END m_axi_rdata_15
  PIN m_axi_rdata_16
    DIRECTION INPUT ;
    USE SIGNAL ;
    ANTENNAGATEAREA 0.647700 ;
    ANTENNADIFFAREA 0.434700 ;
    PORT
      LAYER met2 ;
        RECT 185.930 0.000 186.210 0.280 ;
    END
  END m_axi_rdata_16
  PIN m_axi_rdata_17
    DIRECTION INPUT ;
    USE SIGNAL ;
    ANTENNAGATEAREA 0.647700 ;
    ANTENNADIFFAREA 0.434700 ;
    PORT
      LAYER met3 ;
        RECT 206.450 145.560 207.050 146.160 ;
    END
  END m_axi_rdata_17
  PIN m_axi_rdata_18
    DIRECTION INPUT ;
    USE SIGNAL ;
    ANTENNAGATEAREA 0.647700 ;
    ANTENNADIFFAREA 0.434700 ;
    PORT
      LAYER met3 ;
        RECT 206.450 91.160 207.050 91.760 ;
    END
  END m_axi_rdata_18
  PIN m_axi_rdata_19
    DIRECTION INPUT ;
    USE SIGNAL ;
    ANTENNAGATEAREA 0.647700 ;
    ANTENNADIFFAREA 0.434700 ;
    PORT
      LAYER met3 ;
        RECT 206.450 153.720 207.050 154.320 ;
    END
  END m_axi_rdata_19
  PIN m_axi_rdata_2
    DIRECTION INPUT ;
    USE SIGNAL ;
    ANTENNAGATEAREA 0.647700 ;
    ANTENNADIFFAREA 0.434700 ;
    PORT
      LAYER met3 ;
        RECT 206.450 103.400 207.050 104.000 ;
    END
  END m_axi_rdata_2
  PIN m_axi_rdata_20
    DIRECTION INPUT ;
    USE SIGNAL ;
    ANTENNAGATEAREA 0.647700 ;
    ANTENNADIFFAREA 0.434700 ;
    PORT
      LAYER met3 ;
        RECT 206.450 148.280 207.050 148.880 ;
    END
  END m_axi_rdata_20
  PIN m_axi_rdata_21
    DIRECTION INPUT ;
    USE SIGNAL ;
    ANTENNAGATEAREA 0.647700 ;
    ANTENNADIFFAREA 0.434700 ;
    PORT
      LAYER met3 ;
        RECT 206.450 83.000 207.050 83.600 ;
    END
  END m_axi_rdata_21
  PIN m_axi_rdata_22
    DIRECTION INPUT ;
    USE SIGNAL ;
    ANTENNAGATEAREA 0.647700 ;
    ANTENNADIFFAREA 0.434700 ;
    PORT
      LAYER met3 ;
        RECT 206.450 68.040 207.050 68.640 ;
    END
  END m_axi_rdata_22
  PIN m_axi_rdata_23
    DIRECTION INPUT ;
    USE SIGNAL ;
    ANTENNAGATEAREA 0.647700 ;
    ANTENNADIFFAREA 0.434700 ;
    PORT
      LAYER met3 ;
        RECT 206.450 65.320 207.050 65.920 ;
    END
  END m_axi_rdata_23
  PIN m_axi_rdata_24
    DIRECTION INPUT ;
    USE SIGNAL ;
    ANTENNAGATEAREA 0.647700 ;
    ANTENNADIFFAREA 0.434700 ;
    PORT
      LAYER met2 ;
        RECT 195.130 0.000 195.410 0.280 ;
    END
  END m_axi_rdata_24
  PIN m_axi_rdata_25
    DIRECTION INPUT ;
    USE SIGNAL ;
    ANTENNAGATEAREA 0.647700 ;
    ANTENNADIFFAREA 0.434700 ;
    PORT
      LAYER met3 ;
        RECT 206.450 137.400 207.050 138.000 ;
    END
  END m_axi_rdata_25
  PIN m_axi_rdata_26
    DIRECTION INPUT ;
    USE SIGNAL ;
    ANTENNAGATEAREA 0.647700 ;
    ANTENNADIFFAREA 0.434700 ;
    PORT
      LAYER met3 ;
        RECT 206.450 89.800 207.050 90.400 ;
    END
  END m_axi_rdata_26
  PIN m_axi_rdata_27
    DIRECTION INPUT ;
    USE SIGNAL ;
    ANTENNAGATEAREA 0.647700 ;
    ANTENNADIFFAREA 0.434700 ;
    PORT
      LAYER met2 ;
        RECT 159.250 217.490 159.530 217.770 ;
    END
  END m_axi_rdata_27
  PIN m_axi_rdata_28
    DIRECTION INPUT ;
    USE SIGNAL ;
    ANTENNAGATEAREA 0.647700 ;
    ANTENNADIFFAREA 0.434700 ;
    PORT
      LAYER met3 ;
        RECT 206.450 157.800 207.050 158.400 ;
    END
  END m_axi_rdata_28
  PIN m_axi_rdata_29
    DIRECTION INPUT ;
    USE SIGNAL ;
    ANTENNAGATEAREA 0.647700 ;
    ANTENNADIFFAREA 0.434700 ;
    PORT
      LAYER met3 ;
        RECT 206.450 76.200 207.050 76.800 ;
    END
  END m_axi_rdata_29
  PIN m_axi_rdata_3
    DIRECTION INPUT ;
    USE SIGNAL ;
    ANTENNAGATEAREA 0.647700 ;
    ANTENNADIFFAREA 0.434700 ;
    PORT
      LAYER met2 ;
        RECT 189.610 0.000 189.890 0.280 ;
    END
  END m_axi_rdata_3
  PIN m_axi_rdata_30
    DIRECTION INPUT ;
    USE SIGNAL ;
    ANTENNAGATEAREA 0.647700 ;
    ANTENNADIFFAREA 0.434700 ;
    PORT
      LAYER met2 ;
        RECT 188.690 0.000 188.970 0.280 ;
    END
  END m_axi_rdata_30
  PIN m_axi_rdata_31
    DIRECTION INPUT ;
    USE SIGNAL ;
    ANTENNAGATEAREA 0.647700 ;
    ANTENNADIFFAREA 0.434700 ;
    PORT
      LAYER met3 ;
        RECT 206.450 74.840 207.050 75.440 ;
    END
  END m_axi_rdata_31
  PIN m_axi_rdata_4
    DIRECTION INPUT ;
    USE SIGNAL ;
    ANTENNAGATEAREA 0.647700 ;
    ANTENNADIFFAREA 0.434700 ;
    PORT
      LAYER met3 ;
        RECT 206.450 142.840 207.050 143.440 ;
    END
  END m_axi_rdata_4
  PIN m_axi_rdata_5
    DIRECTION INPUT ;
    USE SIGNAL ;
    ANTENNAGATEAREA 0.647700 ;
    ANTENNADIFFAREA 0.434700 ;
    PORT
      LAYER met3 ;
        RECT 206.450 88.440 207.050 89.040 ;
    END
  END m_axi_rdata_5
  PIN m_axi_rdata_6
    DIRECTION INPUT ;
    USE SIGNAL ;
    ANTENNAGATEAREA 0.647700 ;
    ANTENNADIFFAREA 0.434700 ;
    PORT
      LAYER met3 ;
        RECT 206.450 110.200 207.050 110.800 ;
    END
  END m_axi_rdata_6
  PIN m_axi_rdata_7
    DIRECTION INPUT ;
    USE SIGNAL ;
    ANTENNAGATEAREA 0.647700 ;
    ANTENNADIFFAREA 0.434700 ;
    PORT
      LAYER met3 ;
        RECT 206.450 167.320 207.050 167.920 ;
    END
  END m_axi_rdata_7
  PIN m_axi_rdata_8
    DIRECTION INPUT ;
    USE SIGNAL ;
    ANTENNAGATEAREA 0.647700 ;
    ANTENNADIFFAREA 0.434700 ;
    PORT
      LAYER met3 ;
        RECT 206.450 72.120 207.050 72.720 ;
    END
  END m_axi_rdata_8
  PIN m_axi_rdata_9
    DIRECTION INPUT ;
    USE SIGNAL ;
    ANTENNAGATEAREA 0.647700 ;
    ANTENNADIFFAREA 0.434700 ;
    PORT
      LAYER met3 ;
        RECT 206.450 119.720 207.050 120.320 ;
    END
  END m_axi_rdata_9
  PIN m_axi_rready
    DIRECTION OUTPUT ;
    USE SIGNAL ;
    ANTENNAGATEAREA 0.434700 ;
    ANTENNADIFFAREA 1.137600 ;
    PORT
      LAYER met2 ;
        RECT 192.370 0.000 192.650 0.280 ;
    END
  END m_axi_rready
  PIN m_axi_rresp_0
    DIRECTION INPUT ;
    USE SIGNAL ;
    PORT
      LAYER met2 ;
        RECT 4.690 0.000 4.970 0.280 ;
    END
  END m_axi_rresp_0
  PIN m_axi_rresp_1
    DIRECTION INPUT ;
    USE SIGNAL ;
    PORT
      LAYER met2 ;
        RECT 5.610 0.000 5.890 0.280 ;
    END
  END m_axi_rresp_1
  PIN m_axi_rvalid
    DIRECTION INPUT ;
    USE SIGNAL ;
    ANTENNAGATEAREA 0.647700 ;
    ANTENNADIFFAREA 0.434700 ;
    PORT
      LAYER met2 ;
        RECT 187.770 0.000 188.050 0.280 ;
    END
  END m_axi_rvalid
  PIN m_axi_wdata_0
    DIRECTION OUTPUT ;
    USE SIGNAL ;
    ANTENNAGATEAREA 0.434700 ;
    ANTENNADIFFAREA 1.137600 ;
    PORT
      LAYER met2 ;
        RECT 7.450 217.490 7.730 217.770 ;
    END
  END m_axi_wdata_0
  PIN m_axi_wdata_1
    DIRECTION OUTPUT ;
    USE SIGNAL ;
    ANTENNAGATEAREA 0.434700 ;
    ANTENNADIFFAREA 1.137600 ;
    PORT
      LAYER met3 ;
        RECT 0.000 103.400 0.600 104.000 ;
    END
  END m_axi_wdata_1
  PIN m_axi_wdata_10
    DIRECTION OUTPUT ;
    USE SIGNAL ;
    ANTENNAGATEAREA 0.434700 ;
    ANTENNADIFFAREA 1.137600 ;
    PORT
      LAYER met3 ;
        RECT 0.000 73.480 0.600 74.080 ;
    END
  END m_axi_wdata_10
  PIN m_axi_wdata_11
    DIRECTION OUTPUT ;
    USE SIGNAL ;
    ANTENNAGATEAREA 0.434700 ;
    ANTENNADIFFAREA 1.137600 ;
    PORT
      LAYER met3 ;
        RECT 0.000 57.160 0.600 57.760 ;
    END
  END m_axi_wdata_11
  PIN m_axi_wdata_12
    DIRECTION OUTPUT ;
    USE SIGNAL ;
    ANTENNAGATEAREA 0.434700 ;
    ANTENNADIFFAREA 1.137600 ;
    PORT
      LAYER met3 ;
        RECT 0.000 62.600 0.600 63.200 ;
    END
  END m_axi_wdata_12
  PIN m_axi_wdata_13
    DIRECTION OUTPUT ;
    USE SIGNAL ;
    ANTENNAGATEAREA 0.434700 ;
    ANTENNADIFFAREA 1.137600 ;
    PORT
      LAYER met3 ;
        RECT 0.000 87.080 0.600 87.680 ;
    END
  END m_axi_wdata_13
  PIN m_axi_wdata_14
    DIRECTION OUTPUT ;
    USE SIGNAL ;
    ANTENNAGATEAREA 0.434700 ;
    ANTENNADIFFAREA 1.137600 ;
    PORT
      LAYER met3 ;
        RECT 0.000 34.040 0.600 34.640 ;
    END
  END m_axi_wdata_14
  PIN m_axi_wdata_15
    DIRECTION OUTPUT ;
    USE SIGNAL ;
    ANTENNAGATEAREA 0.434700 ;
    ANTENNADIFFAREA 1.137600 ;
    PORT
      LAYER met3 ;
        RECT 0.000 106.120 0.600 106.720 ;
    END
  END m_axi_wdata_15
  PIN m_axi_wdata_16
    DIRECTION OUTPUT ;
    USE SIGNAL ;
    ANTENNAGATEAREA 0.434700 ;
    ANTENNADIFFAREA 1.137600 ;
    PORT
      LAYER met3 ;
        RECT 0.000 112.920 0.600 113.520 ;
    END
  END m_axi_wdata_16
  PIN m_axi_wdata_17
    DIRECTION OUTPUT ;
    USE SIGNAL ;
    ANTENNAGATEAREA 0.434700 ;
    ANTENNADIFFAREA 1.137600 ;
    PORT
      LAYER met3 ;
        RECT 0.000 149.640 0.600 150.240 ;
    END
  END m_axi_wdata_17
  PIN m_axi_wdata_18
    DIRECTION OUTPUT ;
    USE SIGNAL ;
    ANTENNAGATEAREA 0.434700 ;
    ANTENNADIFFAREA 1.137600 ;
    PORT
      LAYER met2 ;
        RECT 10.210 217.490 10.490 217.770 ;
    END
  END m_axi_wdata_18
  PIN m_axi_wdata_19
    DIRECTION OUTPUT ;
    USE SIGNAL ;
    ANTENNAGATEAREA 0.434700 ;
    ANTENNADIFFAREA 1.137600 ;
    PORT
      LAYER met3 ;
        RECT 0.000 92.520 0.600 93.120 ;
    END
  END m_axi_wdata_19
  PIN m_axi_wdata_2
    DIRECTION OUTPUT ;
    USE SIGNAL ;
    ANTENNAGATEAREA 0.434700 ;
    ANTENNADIFFAREA 1.137600 ;
    PORT
      LAYER met3 ;
        RECT 0.000 134.680 0.600 135.280 ;
    END
  END m_axi_wdata_2
  PIN m_axi_wdata_20
    DIRECTION OUTPUT ;
    USE SIGNAL ;
    ANTENNAGATEAREA 0.434700 ;
    ANTENNADIFFAREA 1.137600 ;
    PORT
      LAYER met3 ;
        RECT 0.000 54.440 0.600 55.040 ;
    END
  END m_axi_wdata_20
  PIN m_axi_wdata_21
    DIRECTION OUTPUT ;
    USE SIGNAL ;
    ANTENNAGATEAREA 0.434700 ;
    ANTENNADIFFAREA 1.137600 ;
    PORT
      LAYER met3 ;
        RECT 0.000 130.600 0.600 131.200 ;
    END
  END m_axi_wdata_21
  PIN m_axi_wdata_22
    DIRECTION OUTPUT ;
    USE SIGNAL ;
    ANTENNAGATEAREA 0.434700 ;
    ANTENNADIFFAREA 1.137600 ;
    PORT
      LAYER met2 ;
        RECT 12.970 217.490 13.250 217.770 ;
    END
  END m_axi_wdata_22
  PIN m_axi_wdata_23
    DIRECTION OUTPUT ;
    USE SIGNAL ;
    ANTENNAGATEAREA 0.434700 ;
    ANTENNADIFFAREA 1.137600 ;
    PORT
      LAYER met3 ;
        RECT 0.000 102.040 0.600 102.640 ;
    END
  END m_axi_wdata_23
  PIN m_axi_wdata_24
    DIRECTION OUTPUT ;
    USE SIGNAL ;
    ANTENNAGATEAREA 0.434700 ;
    ANTENNADIFFAREA 1.137600 ;
    PORT
      LAYER met2 ;
        RECT 40.570 0.000 40.850 0.280 ;
    END
  END m_axi_wdata_24
  PIN m_axi_wdata_25
    DIRECTION OUTPUT ;
    USE SIGNAL ;
    ANTENNAGATEAREA 0.434700 ;
    ANTENNADIFFAREA 1.137600 ;
    PORT
      LAYER met2 ;
        RECT 13.890 217.490 14.170 217.770 ;
    END
  END m_axi_wdata_25
  PIN m_axi_wdata_26
    DIRECTION OUTPUT ;
    USE SIGNAL ;
    ANTENNAGATEAREA 0.434700 ;
    ANTENNADIFFAREA 1.137600 ;
    PORT
      LAYER met3 ;
        RECT 0.000 35.400 0.600 36.000 ;
    END
  END m_axi_wdata_26
  PIN m_axi_wdata_27
    DIRECTION OUTPUT ;
    USE SIGNAL ;
    ANTENNAGATEAREA 0.434700 ;
    ANTENNADIFFAREA 1.137600 ;
    PORT
      LAYER met2 ;
        RECT 17.570 217.490 17.850 217.770 ;
    END
  END m_axi_wdata_27
  PIN m_axi_wdata_28
    DIRECTION OUTPUT ;
    USE SIGNAL ;
    ANTENNAGATEAREA 0.434700 ;
    ANTENNADIFFAREA 1.137600 ;
    PORT
      LAYER met3 ;
        RECT 0.000 115.640 0.600 116.240 ;
    END
  END m_axi_wdata_28
  PIN m_axi_wdata_29
    DIRECTION OUTPUT ;
    USE SIGNAL ;
    ANTENNAGATEAREA 0.434700 ;
    ANTENNADIFFAREA 1.137600 ;
    PORT
      LAYER met3 ;
        RECT 0.000 136.040 0.600 136.640 ;
    END
  END m_axi_wdata_29
  PIN m_axi_wdata_3
    DIRECTION OUTPUT ;
    USE SIGNAL ;
    ANTENNAGATEAREA 0.434700 ;
    ANTENNADIFFAREA 1.137600 ;
    PORT
      LAYER met2 ;
        RECT 20.330 217.490 20.610 217.770 ;
    END
  END m_axi_wdata_3
  PIN m_axi_wdata_30
    DIRECTION OUTPUT ;
    USE SIGNAL ;
    ANTENNAGATEAREA 0.434700 ;
    ANTENNADIFFAREA 1.137600 ;
    PORT
      LAYER met3 ;
        RECT 0.000 127.880 0.600 128.480 ;
    END
  END m_axi_wdata_30
  PIN m_axi_wdata_31
    DIRECTION OUTPUT ;
    USE SIGNAL ;
    ANTENNAGATEAREA 0.434700 ;
    ANTENNADIFFAREA 1.137600 ;
    PORT
      LAYER met3 ;
        RECT 0.000 83.000 0.600 83.600 ;
    END
  END m_axi_wdata_31
  PIN m_axi_wdata_4
    DIRECTION OUTPUT ;
    USE SIGNAL ;
    ANTENNAGATEAREA 0.434700 ;
    ANTENNADIFFAREA 1.137600 ;
    PORT
      LAYER met3 ;
        RECT 0.000 153.720 0.600 154.320 ;
    END
  END m_axi_wdata_4
  PIN m_axi_wdata_5
    DIRECTION OUTPUT ;
    USE SIGNAL ;
    ANTENNAGATEAREA 0.434700 ;
    ANTENNADIFFAREA 1.137600 ;
    PORT
      LAYER met3 ;
        RECT 0.000 59.880 0.600 60.480 ;
    END
  END m_axi_wdata_5
  PIN m_axi_wdata_6
    DIRECTION OUTPUT ;
    USE SIGNAL ;
    ANTENNAGATEAREA 0.434700 ;
    ANTENNADIFFAREA 1.137600 ;
    PORT
      LAYER met3 ;
        RECT 0.000 146.920 0.600 147.520 ;
    END
  END m_axi_wdata_6
  PIN m_axi_wdata_7
    DIRECTION OUTPUT ;
    USE SIGNAL ;
    ANTENNAGATEAREA 0.434700 ;
    ANTENNADIFFAREA 1.137600 ;
    PORT
      LAYER met3 ;
        RECT 0.000 53.080 0.600 53.680 ;
    END
  END m_axi_wdata_7
  PIN m_axi_wdata_8
    DIRECTION OUTPUT ;
    USE SIGNAL ;
    ANTENNAGATEAREA 0.434700 ;
    ANTENNADIFFAREA 1.137600 ;
    PORT
      LAYER met3 ;
        RECT 0.000 80.280 0.600 80.880 ;
    END
  END m_axi_wdata_8
  PIN m_axi_wdata_9
    DIRECTION OUTPUT ;
    USE SIGNAL ;
    ANTENNAGATEAREA 0.434700 ;
    ANTENNADIFFAREA 1.137600 ;
    PORT
      LAYER met2 ;
        RECT 9.290 217.490 9.570 217.770 ;
    END
  END m_axi_wdata_9
  PIN m_axi_wready
    DIRECTION INPUT ;
    USE SIGNAL ;
    ANTENNAGATEAREA 0.647700 ;
    ANTENNADIFFAREA 0.434700 ;
    PORT
      LAYER met2 ;
        RECT 95.770 0.000 96.050 0.280 ;
    END
  END m_axi_wready
  PIN m_axi_wstrb_0
    DIRECTION OUTPUT ;
    USE SIGNAL ;
    ANTENNAGATEAREA 0.434700 ;
    ANTENNADIFFAREA 1.137600 ;
    PORT
      LAYER met2 ;
        RECT 73.690 0.000 73.970 0.280 ;
    END
  END m_axi_wstrb_0
  PIN m_axi_wstrb_1
    DIRECTION OUTPUT ;
    USE SIGNAL ;
    ANTENNAGATEAREA 0.434700 ;
    ANTENNADIFFAREA 1.137600 ;
    PORT
      LAYER met2 ;
        RECT 60.810 0.000 61.090 0.280 ;
    END
  END m_axi_wstrb_1
  PIN m_axi_wstrb_2
    DIRECTION OUTPUT ;
    USE SIGNAL ;
    ANTENNAGATEAREA 0.434700 ;
    ANTENNADIFFAREA 1.137600 ;
    PORT
      LAYER met2 ;
        RECT 44.250 0.000 44.530 0.280 ;
    END
  END m_axi_wstrb_2
  PIN m_axi_wstrb_3
    DIRECTION OUTPUT ;
    USE SIGNAL ;
    ANTENNAGATEAREA 0.434700 ;
    ANTENNADIFFAREA 1.137600 ;
    PORT
      LAYER met2 ;
        RECT 70.010 0.000 70.290 0.280 ;
    END
  END m_axi_wstrb_3
  PIN m_axi_wvalid
    DIRECTION OUTPUT ;
    USE SIGNAL ;
    ANTENNAGATEAREA 0.434700 ;
    ANTENNADIFFAREA 1.137600 ;
    PORT
      LAYER met2 ;
        RECT 94.850 0.000 95.130 0.280 ;
    END
  END m_axi_wvalid
  PIN rst_n
    DIRECTION INPUT ;
    USE SIGNAL ;
    ANTENNAGATEAREA 0.647700 ;
    ANTENNADIFFAREA 0.434700 ;
    PORT
      LAYER met3 ;
        RECT 206.450 23.160 207.050 23.760 ;
    END
  END rst_n
  OBS
      LAYER nwell ;
        RECT 5.330 10.795 201.670 206.805 ;
      LAYER li1 ;
        RECT 5.520 10.795 201.480 206.805 ;
      LAYER met1 ;
        RECT 5.520 9.900 202.330 206.960 ;
      LAYER met2 ;
        RECT 6.070 217.210 6.250 217.490 ;
        RECT 7.090 217.210 7.170 217.490 ;
        RECT 8.010 217.210 8.090 217.490 ;
        RECT 8.930 217.210 9.010 217.490 ;
        RECT 9.850 217.210 9.930 217.490 ;
        RECT 10.770 217.210 10.850 217.490 ;
        RECT 11.690 217.210 11.770 217.490 ;
        RECT 12.610 217.210 12.690 217.490 ;
        RECT 13.530 217.210 13.610 217.490 ;
        RECT 14.450 217.210 14.530 217.490 ;
        RECT 15.370 217.210 15.450 217.490 ;
        RECT 16.290 217.210 16.370 217.490 ;
        RECT 17.210 217.210 17.290 217.490 ;
        RECT 18.130 217.210 18.210 217.490 ;
        RECT 19.050 217.210 19.130 217.490 ;
        RECT 19.970 217.210 20.050 217.490 ;
        RECT 20.890 217.210 62.370 217.490 ;
        RECT 63.210 217.210 63.290 217.490 ;
        RECT 64.130 217.210 65.130 217.490 ;
        RECT 65.970 217.210 66.970 217.490 ;
        RECT 67.810 217.210 79.850 217.490 ;
        RECT 80.690 217.210 80.770 217.490 ;
        RECT 81.610 217.210 82.610 217.490 ;
        RECT 83.450 217.210 83.530 217.490 ;
        RECT 84.370 217.210 84.450 217.490 ;
        RECT 85.290 217.210 85.370 217.490 ;
        RECT 86.210 217.210 89.050 217.490 ;
        RECT 89.890 217.210 91.810 217.490 ;
        RECT 92.650 217.210 92.730 217.490 ;
        RECT 93.570 217.210 99.170 217.490 ;
        RECT 100.010 217.210 100.090 217.490 ;
        RECT 100.930 217.210 101.930 217.490 ;
        RECT 102.770 217.210 102.850 217.490 ;
        RECT 103.690 217.210 103.770 217.490 ;
        RECT 104.610 217.210 104.690 217.490 ;
        RECT 105.530 217.210 112.050 217.490 ;
        RECT 112.890 217.210 113.890 217.490 ;
        RECT 114.730 217.210 114.810 217.490 ;
        RECT 115.650 217.210 115.730 217.490 ;
        RECT 116.570 217.210 117.570 217.490 ;
        RECT 118.410 217.210 118.490 217.490 ;
        RECT 119.330 217.210 119.410 217.490 ;
        RECT 120.250 217.210 120.330 217.490 ;
        RECT 121.170 217.210 121.250 217.490 ;
        RECT 122.090 217.210 134.130 217.490 ;
        RECT 134.970 217.210 135.970 217.490 ;
        RECT 136.810 217.210 136.890 217.490 ;
        RECT 137.730 217.210 137.810 217.490 ;
        RECT 138.650 217.210 138.730 217.490 ;
        RECT 139.570 217.210 139.650 217.490 ;
        RECT 140.490 217.210 140.570 217.490 ;
        RECT 141.410 217.210 141.490 217.490 ;
        RECT 142.330 217.210 142.410 217.490 ;
        RECT 143.250 217.210 158.970 217.490 ;
        RECT 159.810 217.210 159.890 217.490 ;
        RECT 160.730 217.210 162.650 217.490 ;
        RECT 163.490 217.210 163.570 217.490 ;
        RECT 164.410 217.210 202.310 217.490 ;
        RECT 6.070 0.560 202.310 217.210 ;
        RECT 6.170 0.070 37.530 0.560 ;
        RECT 38.370 0.070 40.290 0.560 ;
        RECT 41.130 0.070 43.970 0.560 ;
        RECT 44.810 0.070 59.610 0.560 ;
        RECT 60.450 0.070 60.530 0.560 ;
        RECT 61.370 0.070 61.450 0.560 ;
        RECT 62.290 0.070 64.210 0.560 ;
        RECT 65.050 0.070 65.130 0.560 ;
        RECT 65.970 0.070 66.050 0.560 ;
        RECT 66.890 0.070 69.730 0.560 ;
        RECT 70.570 0.070 73.410 0.560 ;
        RECT 74.250 0.070 80.770 0.560 ;
        RECT 81.610 0.070 81.690 0.560 ;
        RECT 82.530 0.070 82.610 0.560 ;
        RECT 83.450 0.070 83.530 0.560 ;
        RECT 84.370 0.070 84.450 0.560 ;
        RECT 85.290 0.070 85.370 0.560 ;
        RECT 86.210 0.070 86.290 0.560 ;
        RECT 87.130 0.070 87.210 0.560 ;
        RECT 88.050 0.070 88.130 0.560 ;
        RECT 88.970 0.070 93.650 0.560 ;
        RECT 94.490 0.070 94.570 0.560 ;
        RECT 95.410 0.070 95.490 0.560 ;
        RECT 96.330 0.070 96.410 0.560 ;
        RECT 97.250 0.070 97.330 0.560 ;
        RECT 98.170 0.070 98.250 0.560 ;
        RECT 99.090 0.070 99.170 0.560 ;
        RECT 100.010 0.070 101.010 0.560 ;
        RECT 101.850 0.070 103.770 0.560 ;
        RECT 104.610 0.070 104.690 0.560 ;
        RECT 105.530 0.070 106.530 0.560 ;
        RECT 107.370 0.070 109.290 0.560 ;
        RECT 110.130 0.070 110.210 0.560 ;
        RECT 111.050 0.070 118.490 0.560 ;
        RECT 119.330 0.070 119.410 0.560 ;
        RECT 120.250 0.070 121.250 0.560 ;
        RECT 122.090 0.070 122.170 0.560 ;
        RECT 123.010 0.070 123.090 0.560 ;
        RECT 123.930 0.070 124.010 0.560 ;
        RECT 124.850 0.070 128.610 0.560 ;
        RECT 129.450 0.070 185.650 0.560 ;
        RECT 186.490 0.070 186.570 0.560 ;
        RECT 187.410 0.070 187.490 0.560 ;
        RECT 188.330 0.070 188.410 0.560 ;
        RECT 189.250 0.070 189.330 0.560 ;
        RECT 190.170 0.070 190.250 0.560 ;
        RECT 191.090 0.070 191.170 0.560 ;
        RECT 192.010 0.070 192.090 0.560 ;
        RECT 192.930 0.070 193.010 0.560 ;
        RECT 193.850 0.070 193.930 0.560 ;
        RECT 194.770 0.070 194.850 0.560 ;
        RECT 195.690 0.070 195.770 0.560 ;
        RECT 196.610 0.070 202.310 0.560 ;
      LAYER met3 ;
        RECT 0.600 186.000 206.450 206.885 ;
        RECT 1.000 184.600 206.450 186.000 ;
        RECT 0.600 175.120 206.450 184.600 ;
        RECT 0.600 166.920 206.050 175.120 ;
        RECT 0.600 158.800 206.450 166.920 ;
        RECT 0.600 156.040 206.050 158.800 ;
        RECT 0.600 154.720 206.450 156.040 ;
        RECT 1.000 151.960 206.050 154.720 ;
        RECT 1.000 149.280 206.450 151.960 ;
        RECT 1.000 142.440 206.050 149.280 ;
        RECT 0.600 141.080 206.050 142.440 ;
        RECT 0.600 138.400 206.450 141.080 ;
        RECT 1.000 132.920 206.050 138.400 ;
        RECT 1.000 130.240 206.450 132.920 ;
        RECT 1.000 123.400 206.050 130.240 ;
        RECT 0.600 120.720 206.050 123.400 ;
        RECT 1.000 98.920 206.050 120.720 ;
        RECT 0.600 97.600 206.050 98.920 ;
        RECT 1.000 90.760 206.050 97.600 ;
        RECT 0.600 88.080 206.050 90.760 ;
        RECT 1.000 86.680 206.050 88.080 ;
        RECT 1.000 85.360 206.450 86.680 ;
        RECT 1.000 79.880 206.050 85.360 ;
        RECT 0.600 75.840 206.050 79.880 ;
        RECT 1.000 71.720 206.050 75.840 ;
        RECT 0.600 64.960 206.050 71.720 ;
        RECT 1.000 64.920 206.050 64.960 ;
        RECT 1.000 51.320 206.450 64.920 ;
        RECT 0.600 39.120 206.450 51.320 ;
        RECT 1.000 33.640 206.450 39.120 ;
        RECT 0.600 24.160 206.450 33.640 ;
        RECT 0.600 22.760 206.050 24.160 ;
        RECT 0.600 10.715 206.450 22.760 ;
      LAYER met4 ;
        RECT 199.015 26.695 199.345 114.065 ;
  END
END dma_axi_master
END LIBRARY

